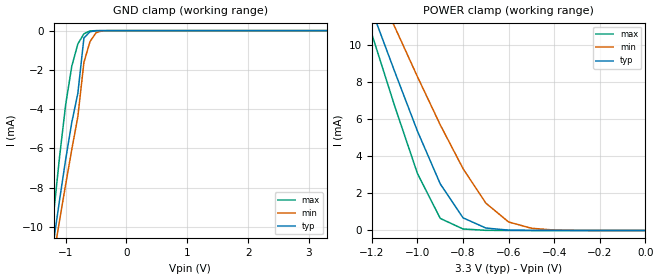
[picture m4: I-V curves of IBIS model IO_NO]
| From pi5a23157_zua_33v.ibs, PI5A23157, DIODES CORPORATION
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[Model]   IO_NO
Model_type   Terminator
C_comp   2.960pF   2.903pF   3.053pF
[Voltage Range]   3.3   3   3.6
[Temperature Range]   25   -40   125
[GND Clamp Reference]   0   0   0
[POWER Clamp Reference]   3.3   3   3.6
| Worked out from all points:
|   GND clamp passes 1 mA (typ) near -0.72 V on its own axis
|   POWER clamp passes 1 mA (typ) near -0.82 V on its own axis
[GND_Clamp]
-3.3V     -3.99A     -4.043A    -4.001A
-1.3V     -12.97mA   -13.79mA   -12.46mA
-1.2V     -10.76mA   -11.55mA   -9.373mA
-1.1V     -8.61mA    -9.653mA   -6.407mA
-1V       -6.55mA    -7.827mA   -3.758mA
-900mV    -4.68mA    -6.057mA   -1.818mA
-800mV    -3.192mA   -4.38mA    -676.3uA
-700mV    -371.8uA   -1.613mA   -161.9uA
-600mV    -59.28uA   -558.3uA   -14.42uA
-500mV    -5.325uA   -105.3uA   -563.4nA
-400mV    -316.2nA   -10.87uA   -13.45nA
3.3V      501.2pA    2.329uA    324.8pA
[Power_Clamp]
-3.3V     55.62mA    46.38mA    65.56mA
-1.3V     15.1mA     16.35mA    14.33mA
-1.2V     11.86mA    13.68mA    10.58mA
-1.1V     8.568mA    10.98mA    6.71mA
-1V       5.353mA    8.288mA    3.067mA
-900mV    2.51mA     5.692mA    650.3uA
-800mV    679.9uA    3.332mA    79.57uA
-700mV    131.6uA    1.473mA    7.874uA
-600mV    19.19uA    456.4uA    573.5nA
-500mV    1.923uA    119.9uA    23.84nA
-400mV    133.2nA    20.66uA    1.87nA
0V        501.6pA    4.144nA    540.8pA
